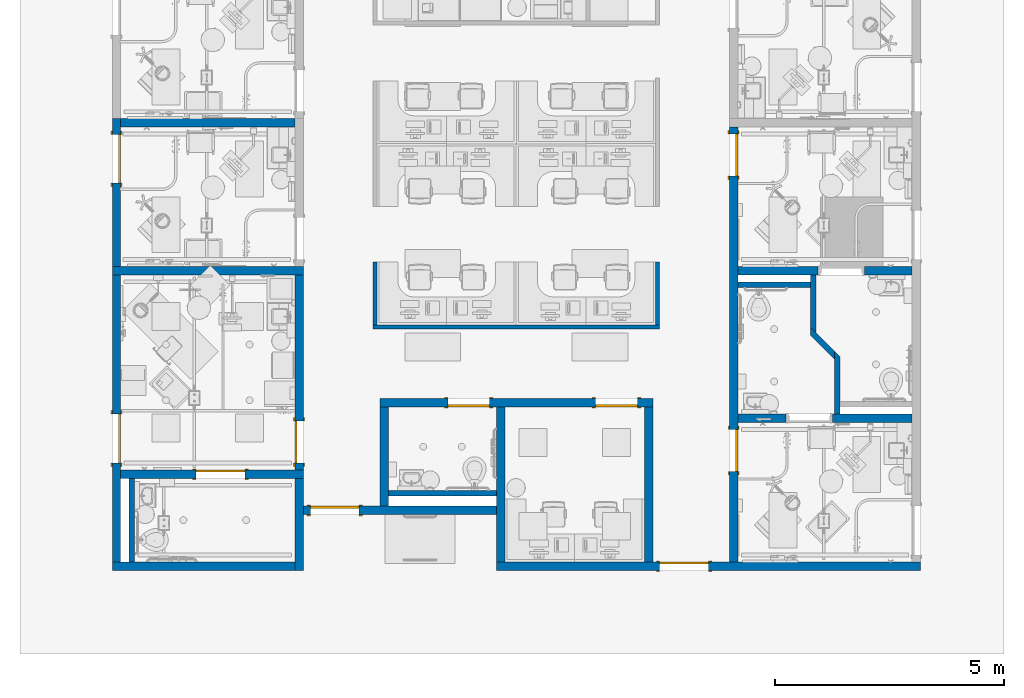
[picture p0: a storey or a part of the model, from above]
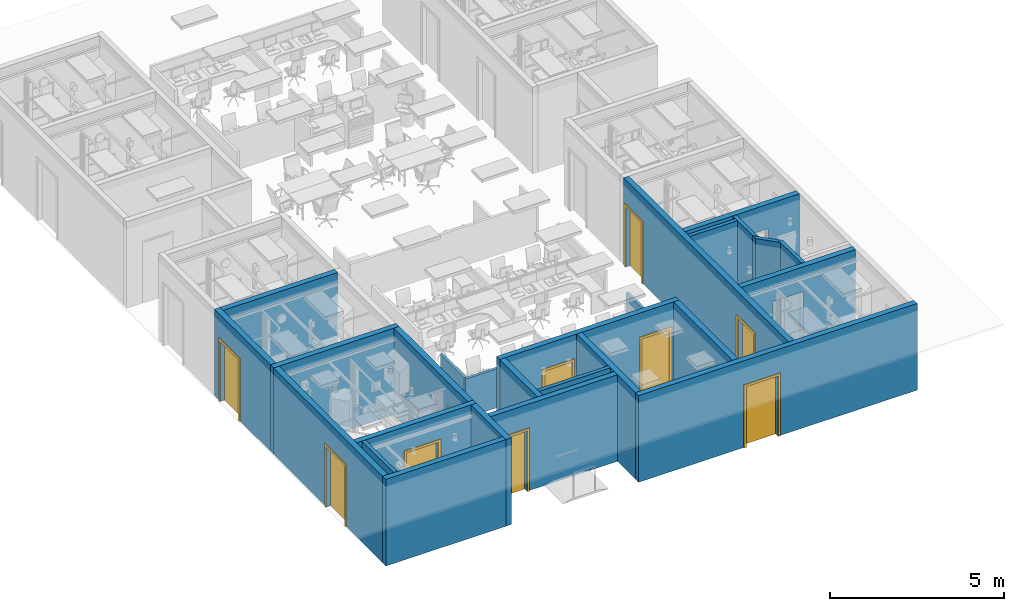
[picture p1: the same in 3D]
Properties of the parts of a building model (IFC2X3)

# File
Description: ViewDefinition [CoordinationView_V2.0]
File name: (ROOM CODE)
Time: 2018-06-28T11:02:34
Author: CF
Organization: Veteran Affairs
Written by: The EXPRESS Data Manager Version 5.02.0100.07 : 28 Aug 2013
Made in: 20170223_1515(x64) - Exporter 18.0.0.420 - Alternate UI 18.0.0.420
Comment: STEP Physical File produced by: The EXPRESS Data Manager Version 5.02.0100.07 : 28 Aug 2013 * Module: EDMstepFileFactory/EDMstandAlone * Creation date: Thu Jun 28 11:02:34 2018 * Host: L106-OKC * Database: C:\Users\BHR~1.SPU\AppData\Local\Temp\{17ECE1BB-D55B-4278-8FE0-BDF93EE0B015}\ifc * Database version: 5507 * Database creation date: Thu Jun 28 11:02:25 2018 * Schema: IFC2X3 * Model: DataRepository.ifc * Model creation date: Thu Jun 28 11:02:25 2018 * Header model: DataRepository.ifc_HeaderModel * Header model creation date: Thu Jun 28 11:02:25 2018 * EDMuser: sdai-user * EDMgroup: sdai-group * License ID and type: 5605 : Permanent license. Expiry date: * EDMstepFileFactory options: 020000

# IfcProject, (ROOM CODE)
LongName: ROOM NAME (ROOM CODE); Phase: DRAFT

# IfcSite, Default
RefLatitude: 42, 21, 31, 181945; RefLongitude: -71, -3, -24, -263305; RefElevation: 0 ft

# IfcBuilding, OUTPATIENT / PACT CLINIC (Ch. 265)
LongName: OUTPATIENT / PACT CLINIC (Ch. 265)
Pset_BuildingCommon - NumberOfStoreys: 1

# IfcBuildingStorey, LEVEL 1
In: OUTPATIENT / PACT CLINIC (Ch. 265)
LongName: LEVEL 1; Elevation: 0 ft

# IfcSpace (25)
In: LEVEL 1
InteriorOrExteriorSpace: INTERNAL
Pset_SpaceCommon - Category: Rooms
Name | LongName | Reference
4 x EXPA01 | EXAM | EXAM EXPA01
3 x TNPG1 | TOILET | TOILET TNPG1
TRPR1 | PROCEDURE | PROCEDURE TRPR1
FA01 | FLEX OFFICE | FLEX OFFICE FA01
UCCL1 | CLEAN | CLEAN UCCL1
3 x WRTM1 | PACT TEAM WORK SPACE | PACT TEAM WORK SPACE WRTM1
2 x RCA01 | EQUIP | EQUIP RCA01
RCA06 | MED ALCOVE | MED ALCOVE RCA06
EXW01 | WOMENS EXAM | WOMENS EXAM EXW01
3 x EXPA1 | EXAM | EXAM EXPA1
EXW01 | WOMEN'S EXAM | WOMEN'S EXAM EXW01
2 x TPG01 | TOILET | TOILET TPG01
PEHW2 | ALCOVE, SCALE | ALCOVE, SCALE PEHW2
RCA02 | COPY ALCOVE | COPY ALCOVE RCA02

# IfcBuildingElementProxy: 24"H x 24"D x 24"W, Z1018 - Cabinet, ADA Sink Support:24"H x 24"D x 24"W:22523303
In: TRPR1
Type - Classification: CC (Uniformat)
Pset_BuildingElementProxyCommon - Reference: 24"H x 24"D x 24"W
Pset_ManufacturerTypeInformation - Manufacturer: Herman Miller, Inc.

# IfcBuildingElementProxy: 24"H x 24"D x 36"W (7)
Type - Classification: CC (Uniformat)
Pset_BuildingElementProxyCommon - Reference: 24"H x 24"D x 36"W
Pset_ManufacturerTypeInformation - Manufacturer: Herman Miller, Inc.
Name (Z1018 - Cabinet, ADA Sink Support:24"H x 24"D x 36"W:...) | In
22479368 | EXPA01
22494769 | EXPA01
22501249 | EXPA01
22501561 | EXPA01
22501847 | EXPA1
22502073 | EXPA1
22502324 | EXPA1

# IfcBuildingElementProxy: A1011 - Telephone, Desk, 1 Line, A1011 - Telephone, Desk, 1 Line:A1011 - Telephone, Desk, 1 Line:22441978
In: RCA02
Type - Classification: VV (Uniformat)
Pset_BuildingElementProxyCommon - Reference: A1011 - Telephone, Desk, 1 Line

# IfcBuildingElementProxy: A1012 - Telephone, Wall Mounted, 1 Line 12'' x 12'' (11)
Pset_BuildingElementProxyCommon - Reference: A1012 - Telephone, Wall Mounted, 1 Line 12'' x 12''
Name (A1012 - Telephone, Wall Mounted, 1 Line 12 x 12:A1012 - Telephone, Wall Mounted, 1 Line 12'' x 12'':...) | In
22169076 | LEVEL 1
22479357 | EXPA01
22494758 | EXPA01
22501238 | EXPA01
22501550 | EXPA01
22501837 | EXPA1
22502063 | EXPA1
22502314 | EXPA1
22503515 | EXW01
22506298 | EXW01
22523292 | TRPR1

# IfcBuildingElementProxy: A1015 - Telephone, Desk, Multiple Line 12 x 12 (22)
Pset_BuildingElementProxyCommon - Reference: A1015 - Telephone, Desk, Multiple Line 12 x 12
Name (A1015 - Telephone, Desk, Multiple Line 12 x 12:A1015 - Telephone, Desk, Multiple Line 12 x 12:...) | In
2989618 | WRTM1
2989619 | WRTM1
2989622 | WRTM1
2989623 | WRTM1
2989626 | WRTM1
2989627 | WRTM1
2989630 | WRTM1
2989631 | WRTM1
2989634 | WRTM1
2989635 | WRTM1
2989638 | WRTM1
2989639 | WRTM1
2989642 | WRTM1
2989643 | WRTM1
2989646 | WRTM1
2989647 | WRTM1
2989650 | WRTM1
2989651 | WRTM1
2989654 | WRTM1
2989655 | WRTM1
22406473 | FA01
22406474 | FA01

# IfcBuildingElementProxy: A1067 - Mirror, Float Glass, ADA Accessible 12"x 6" (5)
Type - Classification: CC (Uniformat)
Pset_BuildingElementProxyCommon - Reference: A1067 - Mirror, Float Glass, ADA Accessible 12"x 6"
Name (A1067 - Mirror, Float Glass, ADA Accessible:A1067 - Mirror, Float Glass, ADA Accessible 12"x 6":...) | In
22452376 | TNPG1
22462786 | TNPG1
22470012 | TPG01
22473208 | TPG01
22527073 | TNPG1

# IfcBuildingElementProxy: A1132 - Rail, Accessory Mounting (10)
Pset_BuildingElementProxyCommon - Reference: A1132 - Rail, Accessory Mounting
Name (A1132 - Rail, Accessory Mounting:A1132 - Rail, Accessory Mounting:...) | In
22479365 | EXPA01
22494766 | EXPA01
22501246 | EXPA01
22501558 | EXPA01
22501844 | EXPA1
22502070 | EXPA1
22502321 | EXPA1
22503522 | EXW01
22506305 | EXW01
22523266 | TRPR1

# IfcBuildingElementProxy: A1203 Lift System, Overhead, Bariatric (11)
Type - Classification: CC (Uniformat)
Pset_BuildingElementProxyCommon - Reference: A1203 Lift System, Overhead, Bariatric
Name (A1203 Lift System, Overhead, Bariatric (Traverse):A1203 Lift System, Overhead, Bariatric:...) | In
22198459 | EXPA01
22499793 | EXPA01
22499953 | TRPR1
22500710 | EXPA01
22500820 | EXPA01
22502521 | EXPA1
22503415 | EXPA1
22505017 | EXPA1
22505114 | EXW01
22506124 | EXW01
22525532 | TNPG1

# IfcBuildingElementProxy: A5075 - Dispenser, Soap (16)
Pset_BuildingElementProxyCommon - Reference: A5075 - Dispenser, Soap
Name (A5075 - Dispenser, Soap:A5075 - Dispenser, Soap:...) | In
22431184 | LEVEL 1
22452375 | TNPG1
22462785 | TNPG1
22470015 | TPG01
22473211 | TPG01
22479348 | EXPA01
22494749 | EXPA01
22501229 | EXPA01
22501541 | EXPA01
22501828 | EXPA1
22502054 | EXPA1
22502305 | EXPA1
22503506 | EXW01
22506289 | EXW01
22523286 | TRPR1
22527072 | TNPG1

# IfcBuildingElementProxy: A5080 - Dispenser, Paper Towel (15)
Pset_BuildingElementProxyCommon - Reference: A5080 - Dispenser, Paper Towel
Name (A5080 - Dispenser, Paper Towel:A5080 - Dispenser, Paper Towel:...) | In
22452374 | TNPG1
22462784 | TNPG1
22470014 | TPG01
22473210 | TPG01
22479349 | EXPA01
22494750 | EXPA01
22501230 | EXPA01
22501542 | EXPA01
22501829 | EXPA1
22502055 | EXPA1
22502306 | EXPA1
22503507 | EXW01
22506290 | EXW01
22523287 | TRPR1
22527071 | TNPG1

# IfcBuildingElementProxy: A5082 - Dispenser, Paper Towel, Sensor, Hands Free, A5082 - Dispenser, Paper Towel, Sensor, Hands Free:A5082 - Dispenser, Paper Towel, Sensor, Hands Free:22431183
In: LEVEL 1
Type - Classification: CC (Uniformat)
Pset_BuildingElementProxyCommon - Reference: A5082 - Dispenser, Paper Towel, Sensor, Hands Free

# IfcBuildingElementProxy: A5090 - Dispenser, Sanitary Napkin, SS, Surface Mounted (3)
In: TNPG1
Pset_BuildingElementProxyCommon - Reference: A5090 - Dispenser, Sanitary Napkin, SS, Surface Mounted
Name | Classification
A5090 - Dispenser, Sanitary Napkin, SS, Surface Mounted:A5090 - Dispenser, Sanitary Napkin, SS, Surface Mounted:22169134
A5090 - Dispenser, Sanitary Napkin, SS, Surface Mounted1:A5090 - Dispenser, Sanitary Napkin, SS, Surface Mounted:22457838 | CC (Uniformat)
A5090 - Dispenser, Sanitary Napkin, SS, Surface Mounted1:A5090 - Dispenser, Sanitary Napkin, SS, Surface Mounted:22462717 | CC (Uniformat)

# IfcBuildingElementProxy: A5090 - Dispenser, Sanitary Napkin, SS, Surface Mounted (2)
In: TPG01
Type - Classification: CC (Uniformat)
Pset_BuildingElementProxyCommon - Reference: A5090 - Dispenser, Sanitary Napkin, SS, Surface Mounted
Name (A5090 - Dispenser, Sanitary Napkin, SS, Surface Mounted1:A5090 - Dispenser, Sanitary Napkin, SS, Surface Mounted:...)
22467408
22473125

# IfcBuildingElementProxy: A5107 - Dispenser, Glove, Surgical-Examination, Wall Mntd 10"x 4" (8)
Classification: VV (Uniformat)
Pset_BuildingElementProxyCommon - Reference: A5107 - Dispenser, Glove, Surgical-Examination, Wall Mntd 10"x 4"
Name (A5107 - Dispenser, Glove, Surgical-Examination, Wall Mntd1:A5107 - Dispenser, Glove, Surgical-Examination, Wall Mntd 10"x 4":...) | In
22479366 | EXPA01
22494767 | EXPA01
22501247 | EXPA01
22501559 | EXPA01
22501845 | EXPA1
22502071 | EXPA1
22502322 | EXPA1
22523294 | TRPR1

# IfcBuildingElementProxy: A5107 - Dispenser, Glove, Surgical-Examination, Wall Mntd 10"x 4" (3)
Type - Classification: VV (Uniformat)
Pset_BuildingElementProxyCommon - Reference: A5107 - Dispenser, Glove, Surgical-Examination, Wall Mntd 10"x 4"
Name (A5107 - Dispenser, Glove, Surgical-Examination, Wall Mntd1:A5107 - Dispenser, Glove, Surgical-Examination, Wall Mntd 10"x 4":...) | In
22431194 | LEVEL 1
22503523 | EXW01
22506306 | EXW01

# IfcBuildingElementProxy: A5108 - Waste Disposal Unit, Sharps 17"x 13" (10)
In: LEVEL 1
Type - Classification: VV (Uniformat)
Pset_BuildingElementProxyCommon - Reference: A5108 - Waste Disposal Unit, Sharps 17"x 13"
Name (A5108 - Waste Disposal Unit, Sharps1:A5108 - Waste Disposal Unit, Sharps 17"x 13":...)
22431193
22479367
22494768
22501248
22501560
22501846
22502072
22502323
22503525
22506308

# IfcBuildingElementProxy: A5109 - Grab Bar, 1.25 in Dia, SS, 2 Wall, W-C Accessible_Improved (8)
Type - Classification: CC (Uniformat)
Pset_BuildingElementProxyCommon - Reference: A5109 - Grab Bar, 1.25 in Dia, SS, 2 Wall, W-C Accessible_Improved
Name (A5109 - Grab Bar, 1.25 in Dia, SS, 2 Wall, W-C Accessible_Improved1:A5109 - Grab Bar, 1.25 in Dia, SS, 2 Wall, W-C Accessible_Improved:...) | In
22457839 | TNPG1
22457842 | TNPG1
22462718 | TNPG1
22462721 | TNPG1
22467409 | TPG01
22467410 | TPG01
22473126 | TPG01
22473127 | TPG01

# IfcBuildingElementProxy: A5109 - Grab Bar, 1.25 in Dia, SS, 2 Wall, W-C Accessible_Improved 2 (2)
In: TNPG1
Type - Classification: CC (Uniformat)
Pset_BuildingElementProxyCommon - Reference: A5109 - Grab Bar, 1.25 in Dia, SS, 2 Wall, W-C Accessible_Improved 2
Name (A5109 - Grab Bar, 1.25 in Dia, SS, 2 Wall, W-C Accessible_Improved1:A5109 - Grab Bar, 1.25 in Dia, SS, 2 Wall, W-C Accessible_Improved 2:...)
22431128
22431129

# IfcBuildingElementProxy: A5145 - Hook, Garment, Double (19)
Type - Classification: CC (Uniformat)
Pset_BuildingElementProxyCommon - Reference: A5145 - Hook, Garment, Double
Name (A5145 - Hook, Garment, Double:A5145 - Hook, Garment, Double:...) | In
22479358 | EXPA01
22479364 | EXPA01
22494759 | EXPA01
22494765 | EXPA01
22501239 | EXPA01
22501245 | EXPA01
22501551 | EXPA01
22501557 | EXPA01
22501838 | EXPA1
22501843 | EXPA1
22502064 | EXPA1
22502069 | EXPA1
22502315 | EXPA1
22502320 | EXPA1
22503516 | EXW01
22503521 | EXW01
22506299 | EXW01
22506304 | EXW01
22523264 | TRPR1

# IfcBuildingElementProxy: A5180 - Track, Cubicle, Surface Mounted, With Curtain, Curved (19)
Type - Classification: CC (Uniformat)
Pset_BuildingElementProxyCommon - Reference: A5180 - Track, Cubicle, Surface Mounted, With Curtain, Curved
Name (A5180 - Track, Cubicle, Surface Mounted, With Curtain, Corner:A5180 - Track, Cubicle, Surface Mounted, With Curtain, Curved:...) | In
22479345 | EXPA01
22479362 | EXPA01
22494746 | EXPA01
22494763 | EXPA01
22500706 | EXPA01
22500707 | EXPA01
22500816 | EXPA01
22500817 | EXPA01
22501537 | EXPA01
22501821 | EXPA1
22501822 | EXPA1
22502298 | EXPA1
22502299 | EXPA1
22503353 | EXPA1
22503354 | EXPA1
22504890 | EXW01
22504891 | EXW01
22506122 | EXW01
22506123 | EXW01

# IfcBuildingElementProxy: A5180 - Track, Cubicle, Surface Mounted, With Curtain, Straight_12'-6", A5180 - Track, Cubicle, Surface Mounted, With Curtain, Straight_12'-6":A5180 - Track, Cubicle, Surface Mounted, With Curtain, Straight_12'-6":22523297
In: TRPR1
Type - Classification: CC (Uniformat)
Pset_BuildingElementProxyCommon - Reference: A5180 - Track, Cubicle, Surface Mounted, With Curtain, Straight_12'-6"

# IfcBuildingElementProxy: A5180 - Track, Cubicle, Surface Mounted, With Curtain, Straight_6-10, A5180 - Track, Cubicle, Surface Mounted, With Curtain, Straight_8'-6":A5180 - Track, Cubicle, Surface Mounted, With Curtain, Straight_6-10:22523304
In: TRPR1
Type - Classification: CC (Uniformat)
Pset_BuildingElementProxyCommon - Reference: A5180 - Track, Cubicle, Surface Mounted, With Curtain, Straight_6-10

# IfcBuildingElementProxy: A5200 - Dispenser, Toilet Tissue, SS, 2-Roll, Surface Mntd (3)
In: TNPG1
Pset_BuildingElementProxyCommon - Reference: A5200 - Dispenser, Toilet Tissue, SS, 2-Roll, Surface Mntd
Name | Classification
A5200 - Dispenser, Toilet Tissue, SS, 2-Roll, Surface Mntd:A5200 - Dispenser, Toilet Tissue, SS, 2-Roll, Surface Mntd:22169137
A5200 - Dispenser, Toilet Tissue, SS, 2-Roll, Surface Mntd1:A5200 - Dispenser, Toilet Tissue, SS, 2-Roll, Surface Mntd:22457840 | CC (Uniformat)
A5200 - Dispenser, Toilet Tissue, SS, 2-Roll, Surface Mntd1:A5200 - Dispenser, Toilet Tissue, SS, 2-Roll, Surface Mntd:22462719 | CC (Uniformat)

# IfcBuildingElementProxy: A5200 - Dispenser, Toilet Tissue, SS, 2-Roll, Surface Mntd (2)
In: TPG01
Type - Classification: CC (Uniformat)
Pset_BuildingElementProxyCommon - Reference: A5200 - Dispenser, Toilet Tissue, SS, 2-Roll, Surface Mntd
Name (A5200 - Dispenser, Toilet Tissue, SS, 2-Roll, Surface Mntd1:A5200 - Dispenser, Toilet Tissue, SS, 2-Roll, Surface Mntd:...)
22467407
22473124

# IfcBuildingElementProxy: C02Q0 - Cabinet, Sink, U-C-B, 1 Door, 36x24x22 LH, C02Q0 - Cabinet, Sink, U-C-B, 1 Door, 36x24x22 LH1:C02Q0 - Cabinet, Sink, U-C-B, 1 Door, 36x24x22 LH:22523299
In: TRPR1
Type - Classification: CC (Uniformat)
Pset_BuildingElementProxyCommon - Reference: C02Q0 - Cabinet, Sink, U-C-B, 1 Door, 36x24x22 LH

# IfcBuildingElementProxy: C04F0 - Cabinet, U-C-B, 1 Shelf, 2 Half DR, 2 DO, 36x36x22 (2)
In: RCA02
Type - Classification: CC (Uniformat)
Pset_BuildingElementProxyCommon - Reference: C04F0 - Cabinet, U-C-B, 1 Shelf, 2 Half DR, 2 DO, 36x36x22
Name (C04F0 - Cabinet, U-C-B, 1 Shelf, 2 Half DR, 2 DO, 36x36x22:C04F0 - Cabinet, U-C-B, 1 Shelf, 2 Half DR, 2 DO, 36x36x22:...)
22441974
22441975

# IfcBuildingElementProxy: CD040 - Cabinet, W-H, 2 Shelf, 2 DO, Sloping Top, 38x36x13 (10)
Type - Classification: CC (Uniformat)
Pset_BuildingElementProxyCommon - Reference: CD040 - Cabinet, W-H, 2 Shelf, 2 DO, Sloping Top, 38x36x13
Name (CD040 - Cabinet, W-H, 2 Shelf, 2 DO, Sloping Top, 38x36x13:CD040 - Cabinet, W-H, 2 Shelf, 2 DO, Sloping Top, 38x36x13:...) | In
22525995 | EXPA01
22526095 | EXPA01
22526146 | EXPA01
22526201 | EXPA01
22526284 | EXPA1
22526415 | EXPA1
22526462 | EXPA1
22526478 | EXW01
22526588 | EXW01
22526604 | TRPR1

# IfcBuildingElementProxy: CS010 - Sink, SS, Single Compartment, 7.5x12x12 ID (11)
Type - Classification: CC (Uniformat)
Pset_BuildingElementProxyCommon - Reference: CS010 - Sink, SS, Single Compartment, 7.5x12x12 ID
Name (CS010 - Sink, SS, Single Compartment, 7.5x12x12 ID1:CS010 - Sink, SS, Single Compartment, 7.5x12x12 ID:...) | In
22431181 | LEVEL 1
22479363 | EXPA01
22494764 | EXPA01
22501244 | EXPA01
22501556 | EXPA01
22501842 | EXPA1
22502068 | EXPA1
22502319 | EXPA1
22503520 | EXW01
22506303 | EXW01
22523288 | TRPR1

# IfcBuildingElementProxy: CT020 - Countertop, Solid Surface (2)
In: EXW01
Type - Classification: CC (Uniformat)
Pset_BuildingElementProxyCommon - Reference: CT020 - Countertop, Solid Surface
Name (CT020 - Countertop, Solid Surface:CT020 - Countertop, Solid Surface:...)
22503519
22506302

# IfcBuildingElementProxy: CT020 - Countertop, Solid Surface - No Opening (2)
Pset_BuildingElementProxyCommon - Reference: CT020 - Countertop, Solid Surface - No Opening
Name (CT020 - Countertop, Solid Surface - No Opening:CT020 - Countertop, Solid Surface - No Opening:...) | In
22441973 | RCA02
22523296 | TRPR1

# IfcBuildingElementProxy: CT020 - Countertop, Solid Surface - No Opening (1) (8)
Type - Classification: CC (Uniformat)
Pset_BuildingElementProxyCommon - Reference: CT020 - Countertop, Solid Surface - No Opening (1)
Name (CT020 - Countertop, Solid Surface - No Opening (1):CT020 - Countertop, Solid Surface - No Opening (1):...) | In
22431180 | LEVEL 1
22479361 | EXPA01
22494762 | EXPA01
22501242 | EXPA01
22501554 | EXPA01
22501841 | EXPA1
22502067 | EXPA1
22502318 | EXPA1

# IfcBuildingElementProxy: E0915 - Locker, Supply, Medication, Wall Mtd, 23W x 20D, E0915 - Locker, Supply, Medication, Wall Mtd, 23W x 20D1:E0915 - Locker, Supply, Medication, Wall Mtd, 23W x 20D:22523302
In: TRPR1
Type - Classification: VV (Uniformat)
Pset_BuildingElementProxyCommon - Reference: E0915 - Locker, Supply, Medication, Wall Mtd, 23W x 20D

# IfcBuildingElementProxy: E0948 - Cart, General Storage, Mobile 42x32x22 (10)
Pset_BuildingElementProxyCommon - Reference: E0948 - Cart, General Storage, Mobile 42x32x22
Name (E0948 - Cart, General Storage, Mobile 42x32x22:E0948 - Cart, General Storage, Mobile 42x32x22:...) | In
22479350 | EXPA01
22494751 | EXPA01
22501231 | EXPA01
22501543 | EXPA01
22501830 | EXPA1
22502056 | EXPA1
22502307 | EXPA1
22503508 | EXW01
22506291 | EXW01
22523267 | TRPR1

# IfcBuildingElementProxy: Exam/Treatment Table with Cabinet (9)
Type - Classification: VV (Uniformat)
Pset_BuildingElementProxyCommon - Reference: Exam/Treatment Table with Cabinet
Name (M9025 - Exam Table1:Exam/Treatment Table with Cabinet:...) | In
22479356 | EXPA01
22494757 | EXPA01
22501237 | EXPA01
22501549 | EXPA01
22501836 | EXPA1
22502062 | EXPA1
22502313 | EXPA1
22503514 | EXW01
22506297 | EXW01

# IfcBuildingElementProxy: F0205 - Chair, Side With Arms (9)
Type - Classification: VV (Uniformat)
Pset_BuildingElementProxyCommon - Reference: F0205 - Chair, Side With Arms
Name (F0205 - Chair, Side With Arms:F0205 - Chair, Side With Arms:...) | In
22479359 | EXPA01
22494760 | EXPA01
22501240 | EXPA01
22501552 | EXPA01
22501839 | EXPA1
22502065 | EXPA1
22502316 | EXPA1
22503517 | EXW01
22506300 | EXW01

# IfcBuildingElementProxy: F0220 - Chair, Conference (4)
In: WRTM1
Classification: VV (Uniformat)
Pset_BuildingElementProxyCommon - Reference: F0220 - Chair, Conference
Name (F0220 - Chair, Conference:F0220 - Chair, Conference:...) | Group
22446537 | Model Group:Model Group Chairs and Tables:22451967
22446540 | Model Group:Model Group Chairs and Tables:22451967
22452117 | Model Group:Model Group Chairs and Tables:22452122
22452118 | Model Group:Model Group Chairs and Tables:22452122

# IfcBuildingElementProxy: F0220 - Chair, Conference (4)
In: WRTM1
Type - Classification: VV (Uniformat)
Pset_BuildingElementProxyCommon - Reference: F0220 - Chair, Conference
Name (F0220 - Chair, Conference:F0220 - Chair, Conference:...) | Group
22446534 | Model Group:Model Group Chairs and Tables:22451967
22451910 | Model Group:Model Group Chairs and Tables:22451967
22452116 | Model Group:Model Group Chairs and Tables:22452122
22452121 | Model Group:Model Group Chairs and Tables:22452122

# IfcBuildingElementProxy: F0275 - Chair, Swivel, High Back (22)
Pset_BuildingElementProxyCommon - Reference: F0275 - Chair, Swivel, High Back
Name (F0275 - Chair, Swivel, High Back:F0275 - Chair, Swivel, High Back:...) | In
3391171 | WRTM1
3391351 | WRTM1
3391371 | WRTM1
3391379 | WRTM1
3391391 | WRTM1
3391399 | WRTM1
3391407 | WRTM1
3391415 | WRTM1
3391477 | WRTM1
3391478 | WRTM1
3391479 | WRTM1
3391480 | WRTM1
3391489 | WRTM1
3391490 | WRTM1
3391491 | WRTM1
3391492 | WRTM1
3391514 | WRTM1
3391570 | WRTM1
3391612 | WRTM1
3391613 | WRTM1
22406477 | FA01
22406478 | FA01

# IfcBuildingElementProxy: F0340 - Stool, Self Adjusting (10)
Pset_BuildingElementProxyCommon - Reference: F0340 - Stool, Self Adjusting
Name (F0340 - Stool, Self Adjusting:F0340 - Stool, Self Adjusting:...) | In
22479351 | EXPA01
22494752 | EXPA01
22501232 | EXPA01
22501544 | EXPA01
22501831 | EXPA1
22502057 | EXPA1
22502308 | EXPA1
22503509 | EXW01
22506292 | EXW01
22523268 | TRPR1

# IfcBuildingElementProxy: F0765 - Table Folding-Nesting (2)
In: WRTM1
Classification: VV (Uniformat)
Pset_BuildingElementProxyCommon - Reference: F0765 - Table Folding-Nesting
Name (F0765 - Table Folding-Nesting:F0765 - Table Folding-Nesting:...) | Group
22446543 | Model Group:Model Group Chairs and Tables:22451967
22452120 | Model Group:Model Group Chairs and Tables:22452122

# IfcBuildingElementProxy: F0765 - Table Folding-Nesting (2)
In: WRTM1
Type - Classification: VV (Uniformat)
Pset_BuildingElementProxyCommon - Reference: F0765 - Table Folding-Nesting
Name (F0765 - Table Folding-Nesting:F0765 - Table Folding-Nesting:...) | Group
22446542 | Model Group:Model Group Chairs and Tables:22451967
22452119 | Model Group:Model Group Chairs and Tables:22452122

# IfcBuildingElementProxy: F2000 - Basket, Wastepaper (20)
Pset_BuildingElementProxyCommon - Reference: F2000 - Basket, Wastepaper
Name (F2000 - Basket, Wastepaper:F2000 - Basket, Wastepaper:...) | In
22078321 | UCCL1
22169139 | TNPG1
22394316 | FA01
22431182 | RCA06
22441971 | RCA02
22452372 | TNPG1
22462782 | TNPG1
22470013 | TPG01
22473209 | TPG01
22479352 | EXPA01
22494753 | EXPA01
22501233 | EXPA01
22501545 | EXPA01
22501832 | EXPA1
22502058 | EXPA1
22502309 | EXPA1
22503510 | EXW01
22506293 | EXW01
22523289 | TRPR1
22527069 | TNPG1

# IfcBuildingElementProxy: F2550 - Shredder, Paper Heavy Duty, F2550 - Shredder, Paper Heavy Duty:F2550 - Shredder, Paper Heavy Duty:22441972
In: RCA02
Type - Classification: VV (Uniformat)
Pset_BuildingElementProxyCommon - Reference: F2550 - Shredder, Paper Heavy Duty

# IfcBuildingElementProxy: F3010 - Board, Bulletin, 18 x 24x 4, F3010 - Board, Bulletin:F3010 - Board, Bulletin, 18 x 24x 4:22523278
In: TRPR1
Type - Classification: VV (Uniformat)
Pset_BuildingElementProxyCommon - Reference: F3010 - Board, Bulletin, 18 x 24x 4

# IfcBuildingElementProxy: F3025 - Board, Bulletin, Wood Framed (12)
In: LEVEL 1
Pset_BuildingElementProxyCommon - Reference: F3025 - Board, Bulletin, Wood Framed
Name (F3025 - Board, Bulletin, Wood Framed:F3025 - Board, Bulletin, Wood Framed:...)
22073912
22075188
22075343
22176911
22501533
22501823
22502043
22502044
22502049
22502294
22502297
22502300

# IfcBuildingElementProxy: F3025 - Board, Bulletin, Wood Framed (9)
Type - Classification: VV (Uniformat)
Pset_BuildingElementProxyCommon - Reference: F3025 - Board, Bulletin, Wood Framed
Name (F3025 - Board, Bulletin, Wood Framed1:F3025 - Board, Bulletin, Wood Framed:...) | In
22479346 | EXPA01
22494747 | EXPA01
22501227 | EXPA01
22501539 | EXPA01
22501826 | EXPA1
22502052 | EXPA1
22502303 | EXPA1
22503505 | EXW01
22506288 | EXW01

# IfcBuildingElementProxy: F3200 - Clock, Battery, 12in Dia (10)
Type - Classification: VV (Uniformat)
Pset_BuildingElementProxyCommon - Reference: F3200 - Clock, Battery, 12in Dia
Name (F3200 - Clock, Battery, 12in Dia:F3200 - Clock, Battery, 12in Dia:...) | In
22479353 | EXPA01
22494754 | EXPA01
22501234 | EXPA01
22501546 | EXPA01
22501833 | EXPA1
22502059 | EXPA1
22502310 | EXPA1
22503511 | EXW01
22506294 | EXW01
22523269 | TRPR1

# IfcBuildingElementProxy: Hoist (11)
Pset_BuildingElementProxyCommon - Reference: Hoist
Name (Hoist:Hoist:...) | In
22499200 | EXPA01
22499794 | EXPA01
22499954 | TRPR1
22500711 | EXPA01
22500821 | EXPA01
22502522 | EXPA1
22503416 | EXPA1
22505018 | EXPA1
22505115 | EXW01
22506125 | EXW01
22525533 | TNPG1

# IfcBuildingElementProxy: M1801 - Computer with Flat Panel Monitor (22)
Pset_BuildingElementProxyCommon - Reference: M1801 - Computer with Flat Panel Monitor
Name (M1801 - Computer with Flat Panel Monitor:M1801 - Computer with Flat Panel Monitor:...) | In
2989620 | WRTM1
2989621 | WRTM1
2989624 | WRTM1
2989625 | WRTM1
2989628 | WRTM1
2989629 | WRTM1
2989632 | WRTM1
2989633 | WRTM1
2989636 | WRTM1
2989637 | WRTM1
2989640 | WRTM1
2989641 | WRTM1
2989644 | WRTM1
2989645 | WRTM1
2989648 | WRTM1
2989649 | WRTM1
2989652 | WRTM1
2989653 | WRTM1
2989656 | WRTM1
2989657 | WRTM1
22406475 | FA01
22406476 | FA01

# IfcBuildingElementProxy: M1801 - Computer with Flat Panel Monitor (10)
Type - Classification: VV (Uniformat)
Pset_BuildingElementProxyCommon - Reference: M1801 - Computer with Flat Panel Monitor
Name (M1801 - Computer with Flat Panel Monitor1:M1801 - Computer with Flat Panel Monitor:...) | In
22479344 | EXPA01
22494745 | EXPA01
22501225 | EXPA01
22501538 | EXPA01
22501825 | EXPA1
22502051 | EXPA1
22502302 | EXPA1
22503503 | EXW01
22506287 | EXW01
22523270 | TRPR1

# IfcBuildingElementProxy: M1801 - Computer with Flat Panel Monitor 2, M1801 - Computer with Flat Panel Monitor1:M1801 - Computer with Flat Panel Monitor 2:22431187
In: RCA06
Type - Classification: VV (Uniformat)
Pset_BuildingElementProxyCommon - Reference: M1801 - Computer with Flat Panel Monitor 2

# IfcBuildingElementProxy: M1802 - Workstation, Computer, Retractable, M1802 - Workstation, Computer, Retractable:M1802 - Workstation, Computer, Retractable:22523271
In: TRPR1
Type - Classification: VV (Uniformat)
Pset_BuildingElementProxyCommon - Reference: M1802 - Workstation, Computer, Retractable

# IfcBuildingElementProxy: M1803 - Workstation, Computer, Wall Mounted (10)
Type - Classification: VV (Uniformat)
Pset_BuildingElementProxyCommon - Reference: M1803 - Workstation, Computer, Wall Mounted
Name (M1803 - Workstation, Computer, Wall Mounted1:M1803 - Workstation, Computer, Wall Mounted:...) | In
22431186 | RCA06
22479360 | EXPA01
22494761 | EXPA01
22501241 | EXPA01
22501553 | EXPA01
22501840 | EXPA1
22502066 | EXPA1
22502317 | EXPA1
22503518 | EXW01
22506301 | EXW01

# IfcBuildingElementProxy: M1810 - Copier, Floor Standing, Digital 42"x 27", M1810 - Copier Floor Standing Digital:M1810 - Copier, Floor Standing, Digital 42"x 27":22441976
In: RCA02
Type - Classification: VV (Uniformat); Material: Plastic - Gray,Dark, Plastic - White
Pset_BuildingElementProxyCommon - Reference: M1810 - Copier, Floor Standing, Digital 42"x 27"

# IfcBuildingElementProxy: M3070 - Hamper, Linen, Mobile, w-Lid, M3070 - Hamper, Linen, Mobile, w-Lid:M3070 - Hamper, Linen, Mobile, w-Lid:22523300
In: TRPR1
Pset_BuildingElementProxyCommon - Reference: M3070 - Hamper, Linen, Mobile, w-Lid

# IfcBuildingElementProxy: M3072 - Frame, Infectious Waste Bag with Lid, M3072 - Frame, Infectious Waste Bag with Lid:M3072 - Frame, Infectious Waste Bag with Lid:22523272
In: TRPR1
Pset_BuildingElementProxyCommon - Reference: M3072 - Frame, Infectious Waste Bag with Lid

# IfcBuildingElementProxy: M3150 - Distribution System, Medication, Automatic 2, M3150 - Distribution System, Medication, Automatic1:M3150 - Distribution System, Medication, Automatic 2:22431188
In: RCA06
Type - Classification: VV (Uniformat)
Pset_BuildingElementProxyCommon - Reference: M3150 - Distribution System, Medication, Automatic 2

# IfcBuildingElementProxy: M4020 - Scale, Person Weighing, High Capacity, M4020 - Scale, Person Weighing, High Capacity:M4020 - Scale, Person Weighing, High Capacity:22366365
In: PEHW2
Type - Classification: VV (Uniformat)
Pset_BuildingElementProxyCommon - Reference: M4020 - Scale, Person Weighing, High Capacity

# IfcBuildingElementProxy: M4100 - Sphygmomanometer, Aneroid, Wall-Mounted (10)
Type - Classification: VV (Uniformat)
Pset_BuildingElementProxyCommon - Reference: M4100 - Sphygmomanometer, Aneroid, Wall-Mounted
Name (M4100 - Sphygmomanometer, Aneroid, Wall-Mounted1:M4100 - Sphygmomanometer, Aneroid, Wall-Mounted:...) | In
22479354 | EXPA01
22494755 | EXPA01
22501235 | EXPA01
22501547 | EXPA01
22501834 | EXPA1
22502060 | EXPA1
22502311 | EXPA1
22503512 | EXW01
22506295 | EXW01
22523273 | TRPR1

# IfcBuildingElementProxy: M4116 - Monitor, Vital Signs, On Mobile Stand, M4116 - Monitor, Vital Signs, On Mobile Stand1:M4116 - Monitor, Vital Signs, On Mobile Stand:22523274
In: TRPR1
Type - Classification: VV (Uniformat)
Pset_BuildingElementProxyCommon - Reference: M4116 - Monitor, Vital Signs, On Mobile Stand

# IfcBuildingElementProxy: M4200 - Otoscope_Ophthalmoscope, Wall Mounted (10)
Type - Classification: VV (Uniformat)
Pset_BuildingElementProxyCommon - Reference: M4200 - Otoscope_Ophthalmoscope, Wall Mounted
Name (M4200 - Otoscope_Ophthalmoscope, Wall Mounted1:M4200 - Otoscope_Ophthalmoscope, Wall Mounted:...) | In
22479355 | EXPA01
22494756 | EXPA01
22501236 | EXPA01
22501548 | EXPA01
22501835 | EXPA1
22502061 | EXPA1
22502312 | EXPA1
22503513 | EXW01
22506296 | EXW01
22523293 | TRPR1

# IfcBuildingElementProxy: M4255 - Stand, IV, Adjustable, M4255 - Stand, IV, Adjustable:M4255 - Stand, IV, Adjustable:22523275
In: TRPR1
Pset_BuildingElementProxyCommon - Reference: M4255 - Stand, IV, Adjustable

# IfcBuildingElementProxy: M4655 - Stretcher, Mobile, CRS, 9 Position, M4655 - Stretcher, Mobile, CRS, 9 Position1:M4655 - Stretcher, Mobile, CRS, 9 Position:22523301
In: TRPR1
Type - Classification: VV (Uniformat)
Pset_BuildingElementProxyCommon - Reference: M4655 - Stretcher, Mobile, CRS, 9 Position

# IfcBuildingElementProxy: M7415 - Light Exam Wall Mounted, M7415 - Light Exam Wall Mounted:M7415 - Light Exam Wall Mounted:22523295
In: TRPR1
Type - Classification: VC (Uniformat)
Pset_BuildingElementProxyCommon - Reference: M7415 - Light Exam Wall Mounted

# IfcBuildingElementProxy: M7710 - Electrocardiograph, 12 Lead, Portable w-no cart, M7710 - Electrocardiograph, 12 Lead, Portable w-no cart1:M7710 - Electrocardiograph, 12 Lead, Portable w-no cart:22523290
In: TRPR1
Classification: VV (Uniformat)
Pset_BuildingElementProxyCommon - Reference: M7710 - Electrocardiograph, 12 Lead, Portable w-no cart

# IfcBuildingElementProxy: M8810 - Stand, Mayo, M8810 - Stand, Mayo1:M8810 - Stand, Mayo:22523276
In: TRPR1
Type - Classification: VV (Uniformat)
Pset_BuildingElementProxyCommon - Reference: M8810 - Stand, Mayo

# IfcBuildingElementProxy: Mobile Spotlight, Mobile Stand (9)
Pset_BuildingElementProxyCommon - Reference: Mobile Spotlight, Mobile Stand
Name (M7401 - Exam Light:Mobile Spotlight, Mobile Stand:...) | In
22479347 | EXPA01
22494748 | EXPA01
22501228 | EXPA01
22501540 | EXPA01
22501827 | EXPA1
22502053 | EXPA1
22502304 | EXPA1
22503524 | EXW01
22506307 | EXW01

# IfcBuildingElementProxy: P3100 - Lavatory, Viteous China (5)
Type - Classification: CC (Uniformat)
Pset_BuildingElementProxyCommon - Reference: P3100 - Lavatory, Viteous China
Name (P3100 - Lavatory, Vitreous China:P3100 - Lavatory, Viteous China:...) | In
22452373 | TNPG1
22462783 | TNPG1
22470011 | TPG01
22473207 | TPG01
22527070 | TNPG1

# IfcBuildingElementProxy: P8710 - Utility Center, Plumbing Connection, P8710 - Utility Center, Plumbing Connection:P8710 - Utility Center, Plumbing Connection:22078322
In: LEVEL 1
Pset_BuildingElementProxyCommon - Reference: P8710 - Utility Center, Plumbing Connection

# IfcBuildingElementProxy: P9050 - Toilet, Wall Hung, Siphon Jet (3)
In: TNPG1
Pset_BuildingElementProxyCommon - Reference: P9050 - Toilet, Wall Hung, Siphon Jet
Name | Classification
P9050 - Toilet, Wall Hung, Siphon Jet:P9050 - Toilet, Wall Hung, Siphon Jet:22169138
P9050 - Toilet, Wall Hung, Siphon Jet1:P9050 - Toilet, Wall Hung, Siphon Jet:22457841 | CC (Uniformat)
P9050 - Toilet, Wall Hung, Siphon Jet1:P9050 - Toilet, Wall Hung, Siphon Jet:22462720 | CC (Uniformat)

# IfcBuildingElementProxy: P9050 - Toilet, Wall Hung, Siphon Jet (2)
In: TPG01
Type - Classification: CC (Uniformat)
Pset_BuildingElementProxyCommon - Reference: P9050 - Toilet, Wall Hung, Siphon Jet
Name (P9050 - Toilet, Wall Hung, Siphon Jet2:P9050 - Toilet, Wall Hung, Siphon Jet:...)
22467406
22473123

# IfcBuildingElementProxy: R6200 - Refrigerator, U-C or F-S, 5 Cu Ft (1), R6200 - Refrigerator, U-C or F-S, 5 Cu Ft (1):R6200 - Refrigerator, U-C or F-S, 5 Cu Ft (1):22431185
In: RCA06
Type - Classification: VV (Uniformat)
Pset_BuildingElementProxyCommon - Reference: R6200 - Refrigerator, U-C or F-S, 5 Cu Ft (1)

# IfcBuildingElementProxy: U0075 - Workstation, L-Shaped, Freestanding, 60x54 (22)
Pset_BuildingElementProxyCommon - Reference: U0075 - Workstation, L-Shaped, Freestanding, 60x54
Name (U0075 - Workstation, L-Shaped, Freestanding, 60x54:U0075 - Workstation, L-Shaped, Freestanding, 60x54:...) | In
2989323 | WRTM1
2989324 | WRTM1
2989325 | WRTM1
2989326 | WRTM1
2989327 | WRTM1
2989328 | WRTM1
2989329 | WRTM1
2989330 | WRTM1
2989340 | WRTM1
2989341 | WRTM1
2989342 | WRTM1
2989343 | WRTM1
2989344 | WRTM1
2989345 | WRTM1
2989346 | WRTM1
2989347 | WRTM1
2989354 | WRTM1
2989355 | WRTM1
2989358 | WRTM1
2989359 | WRTM1
22406471 | FA01
22406472 | FA01

# IfcCovering: Compound Ceiling:2' x 2' ACT System (13)
In: LEVEL 1
PredefinedType: CEILING; Classification: C3030210 Suspended Ceilings - Acoustical (Uniformat); Material: <Unnamed> 0.135417 ft, Acoustic Ceiling Tile 24 x 24 0.0520833 ft
Pset_CoveringCommon - Reference: 2' x 2' ACT System; Finish: Acoustic Ceiling Tile 24 x 24;; TotalThickness: 0.1875 ft
Name (Compound Ceiling:2' x 2' ACT System:...)
3370529
3371161
3504993
3505078
3505124
3505157
3505186
3505211
22168832
22168839
22168846
22168860
22175718

# IfcCovering: Compound Ceiling:GWB on Mtl. Stud (4)
In: LEVEL 1
PredefinedType: CEILING; Classification: C3030220 Suspended Ceilings - Gypsum Board (Uniformat); Material: <Unnamed> 0.302083 ft, Gypsum Wallboard 0.0520833 ft
Pset_CoveringCommon - Reference: GWB on Mtl. Stud; Finish: Gypsum Wallboard;; TotalThickness: 0.354167 ft
Name (Compound Ceiling:GWB on Mtl. Stud:...)
3504863
22168867
22168876
22168885

# IfcDoor: 36" x 84" (12)
In: LEVEL 1
Type - OperationType: SINGLE_SWING_LEFT; ParameterTakesPrecedence: no; Sizeable: no; Classification: C1020 Interior Doors (Uniformat)
Type - DOOR-Design-SGL:36" x 84":2989262 - PanelOperation: SWINGING
OverallHeight: 7 ft; OverallWidth: 3 ft
Pset_DoorCommon - IsExternal: no; Reference: 36" x 84"; ThermalTransmittance: 3.7021 kg/K/s3
Name (DOOR-Design-SGL:36" x 84":...)
2989262
22076974
22077622
22077844
22077982
22078101
22168896
22168940
22168984
22169026
22169069
22408933

# IfcDoor: 36" x 84", DOOR-Design-SGL:36" x 84":22169140
In: LEVEL 1
Type - OperationType: SINGLE_SWING_RIGHT; ParameterTakesPrecedence: no; Sizeable: no; Classification: C1020 Interior Doors (Uniformat)
Type - DOOR-Design-SGL:36" x 84":22169140 - PanelOperation: SWINGING
OverallHeight: 7 ft; OverallWidth: 3 ft
Pset_DoorCommon - IsExternal: no; Reference: 36" x 84"; ThermalTransmittance: 3.7021 kg/K/s3

# IfcDoor: 36" x 84", Door - 180 Degree:36" x 84":22078304
In: LEVEL 1
Type - ParameterTakesPrecedence: no; Sizeable: no; Classification: C1020 Interior Doors (Uniformat)
OverallHeight: 7 ft; OverallWidth: 3 ft
Pset_DoorCommon - IsExternal: no; Reference: 36" x 84"

# IfcDoor: 42" x 84" (11)
In: LEVEL 1
Type - OperationType: SINGLE_SWING_LEFT; ParameterTakesPrecedence: no; Sizeable: no; Classification: C1020 Interior Doors (Uniformat)
Type - DOOR-Design-SGL:42" x 84":2989236 - PanelOperation: SWINGING
OverallHeight: 7 ft; OverallWidth: 3.5 ft
Pset_DoorCommon - Reference: 42" x 84"; IsExternal: no; ThermalTransmittance: 3.7021 kg/K/s3
Name (DOOR-Design-SGL:42" x 84":...)
2989236
2989237
22077624
22077846
22077980
22078103
22168894
22168938
22168983
22169027
22169068

# IfcDoor: 42" x 84" (4)
In: LEVEL 1
Type - OperationType: SINGLE_SWING_RIGHT; ParameterTakesPrecedence: no; Sizeable: no; Classification: C1020 Interior Doors (Uniformat)
Type - DOOR-Design-SGL:42" x 84":2989472 - PanelOperation: SWINGING
OverallHeight: 7 ft; OverallWidth: 3.5 ft
Pset_DoorCommon - Reference: 42" x 84"; IsExternal: no; ThermalTransmittance: 3.7021 kg/K/s3
Name (DOOR-Design-SGL:42" x 84":...)
2989472
22076971
22076975
22168812

# IfcDoor: F 36"x 84" (2)
In: LEVEL 1
Type - ParameterTakesPrecedence: no; Sizeable: no
OverallHeight: 7.16667 ft; OverallWidth: 3.33333 ft
Pset_DoorCommon - IsExternal: no; Reference: F 36"x 84"
Name (DOOR-Hinged-SGL:F 36"x 84":...)
22169023
22169065

# IfcFlowTerminal: 2'x2' (8)
Type - Classification: D5020210 Lighting - Fluorescent (Uniformat)
Pset_DistributionFlowElementCommon - Reference: 2'x2'
Name (Troffer Light:2'x2':...) | In
3481951 | FA01
22525382 | FA01
22525432 | FA01
22525437 | FA01
22529491 | TRPR1
22529948 | TRPR1
22531025 | TRPR1
22531026 | TRPR1

# IfcFlowTerminal: 2'x4' (41)
Type - Classification: D5020210 Lighting - Fluorescent (Uniformat)
Pset_DistributionFlowElementCommon - Reference: 2'x4'
Name (Troffer Light:2'x4':...) | In
22144061 | WRTM1
22144146 | WRTM1
22144189 | WRTM1
22144232 | WRTM1
22144275 | RCA02
22144322 | RCA01
22144365 | WRTM1
22144410 | WRTM1
22144455 | WRTM1
22144498 | WRTM1
22144541 | WRTM1
22144586 | WRTM1
22144631 | WRTM1
22144676 | WRTM1
22144721 | WRTM1
22144764 | WRTM1
22144807 | WRTM1
22144852 | WRTM1
22145214 | WRTM1
22145257 | WRTM1
22168890 | EXW01
22175782 | EXPA1
22175790 | EXPA1
22176820 | EXW01
22184936 | EXPA01
22184937 | EXPA01
22185159 | UCCL1
22376404 | LEVEL 1
22499791 | EXPA01
22499792 | EXPA01
22500708 | EXPA01
22500709 | EXPA01
22500818 | EXPA01
22500819 | EXPA01
22502519 | EXPA1
22502520 | EXPA1
22503479 | EXPA1
22503480 | EXPA1
22506118 | EXW01
22506119 | EXW01
22532010 | LEVEL 1

# IfcFlowTerminal: 6" (14)
Type - Classification: D5020220 Lighting - Incandescent (Uniformat)
Pset_DistributionFlowElementCommon - Reference: 6"
Name (Downlight - Recessed Can1:6":...) | In
22175950 | TNPG1
22472486 | TNPG1
22477965 | TNPG1
22478137 | TNPG1
22478302 | TNPG1
22478303 | TNPG1
22505245 | TPG01
22505305 | TPG01
22505911 | LEVEL 1
22505912 | LEVEL 1
22530866 | TRPR1
22530927 | TRPR1
22530978 | TRPR1
22530979 | TRPR1

# IfcWallStandardCase: Basic Wall:Interior - 4 7/8" (8)
In: LEVEL 1
Type - PredefinedType: STANDARD; Material: <Unnamed> 0.40625 ft
Classification: B2010 Exterior Walls (Uniformat)
Pset_WallCommon - LoadBearing: no; ExtendToStructure: no; IsExternal: yes; Reference: Interior - 4 7/8"
Name (Basic Wall:Interior - 4 7/8":...)
22080859
22169106
22169107
22169108
22169109
22169110
22169130
22462484

# IfcWallStandardCase: Basic Wall:Interior - 7 1/4" (39)
In: LEVEL 1
Type - PredefinedType: STANDARD; Material: <Unnamed> 0.604167 ft
Classification: B2010 Exterior Walls (Uniformat)
Pset_WallCommon - Reference: Interior - 7 1/4"; LoadBearing: no; ExtendToStructure: no; IsExternal: yes
Name (Basic Wall:Interior - 7 1/4":...)
2989175
2989258
2989259
2989261
2989438
22076969
22076970
22076972
22076973
22077619
22077620
22077621
22077841
22077842
22077843
22077977
22077978
22077979
22077981
22078100
22078300
22080858
22080860
22168811
22168891
22168892
22168893
22168895
22168939
22168980
22168982
22169022
22169028
22169064
22169066
22169067
22169070
22169129
22408903

# IfcWallStandardCase: Basic Wall:Systems Furniture Partition (18)
In: LEVEL 1
Type - PredefinedType: STANDARD; Material: <Unnamed> 0.291667 ft
Classification: B2010 Exterior Walls (Uniformat)
Pset_WallCommon - LoadBearing: no; ExtendToStructure: no; IsExternal: yes; Reference: Systems Furniture Partition
Name (Basic Wall:Systems Furniture Partition:...)
2989283
2989318
2989361
2989363
2989364
22361294
22361425
22362213
22362214
22362215
22370068
22370115
22370317
22370337
22422727
22422796
22544395
22544571
